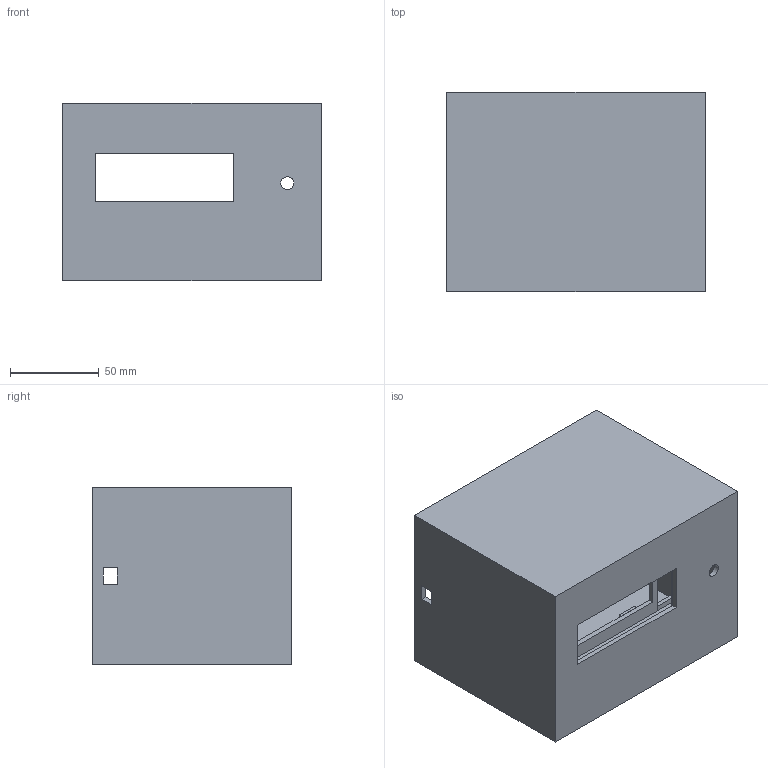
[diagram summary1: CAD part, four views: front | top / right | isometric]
STEP (ISO 10303-21) file: header records copied from the file, then geometry measured from it (millimetres).
FILE_DESCRIPTION(('Open CASCADE Model'),'2;1');
FILE_NAME('Open CASCADE Shape Model','2026-11-04T18:24:45',('Author'),( 'Open CASCADE'),'Open CASCADE STEP processor 7.8','Open CASCADE 7.8' ,'Unknown');
FILE_SCHEMA(('AUTOMOTIVE_DESIGN { 1 0 10303 214 1 1 1 1 }'));
Length unit declared in the file: millimetre
Products named in the file (1): Open CASCADE STEP translator 7.8 1
Bounding box: 145 x 112 x 100 mm (x, y, z)
Volume: 214904.8 mm3; surface area: 153854.1 mm2
Topology: 1 solids, 1 shells, 170 faces, 473 edges, 314 vertices
Faces by surface type: plane 169, cylinder 1
Full cylindrical faces by diameter (mm): 7.2 x1
Entity records: 11218 total; most frequent: CARTESIAN_POINT 2220, DIRECTION 1447, LINE 1099, VECTOR 1099, ORIENTED_EDGE 946, PCURVE 946, DEFINITIONAL_REPRESENTATION 946, EDGE_CURVE 473
